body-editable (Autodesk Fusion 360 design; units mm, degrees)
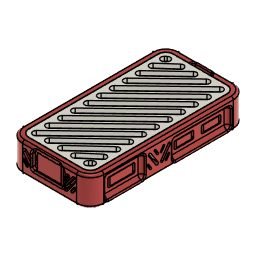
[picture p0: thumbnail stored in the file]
named bodies: "Body", "Cover"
